One B-rep face of a CAD part: STEP entity #190.
In plain terms, the planar face has unit normal (1, 0, 0).
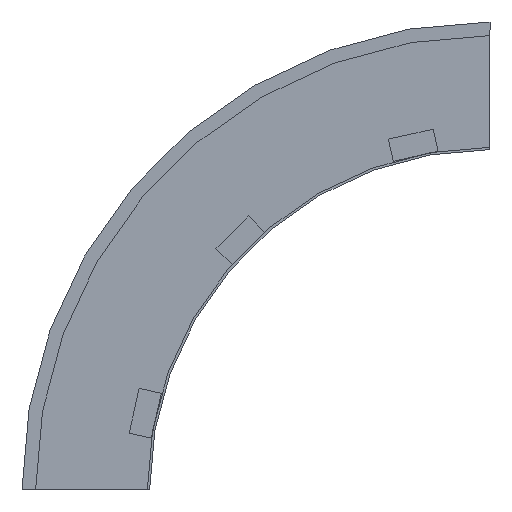
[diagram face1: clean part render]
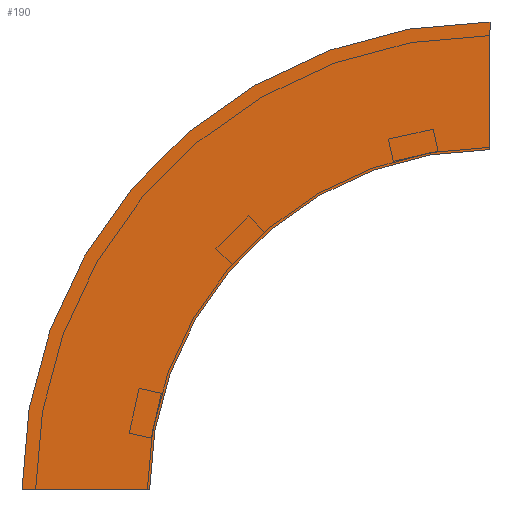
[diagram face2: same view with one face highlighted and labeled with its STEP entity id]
Its self-contained STEP definition (entity closure, numbers rounded to 3 decimals):
#4 = ORIENTED_EDGE ( 'NONE', *, *, #119, .F. ) ;
#8 = ORIENTED_EDGE ( 'NONE', *, *, #198, .T. ) ;
#22 = CARTESIAN_POINT ( 'NONE',  ( 0., 112.5, 0. ) ) ;
#48 = VERTEX_POINT ( 'NONE', #54 ) ;
#54 = CARTESIAN_POINT ( 'NONE',  ( 0., -300., 412.5 ) ) ;
#63 = DIRECTION ( 'NONE',  ( 0., 0., 1. ) ) ;
#70 = CIRCLE ( 'NONE', #253, 412.5 ) ;
#89 = AXIS2_PLACEMENT_3D ( 'NONE', #239, #536, #232 ) ;
#93 = CARTESIAN_POINT ( 'NONE',  ( 0., 0., 0. ) ) ;
#114 = VECTOR ( 'NONE', #139, 1000. ) ;
#118 = EDGE_LOOP ( 'NONE', ( #8, #143, #4, #365 ) ) ;
#119 = EDGE_CURVE ( 'NONE', #565, #291, #509, .T. ) ;
#132 = CARTESIAN_POINT ( 'NONE',  ( 0., 0., 0. ) ) ;
#136 = EDGE_CURVE ( 'NONE', #291, #48, #478, .T. ) ;
#139 = DIRECTION ( 'NONE',  ( 0., 1., 0. ) ) ;
#143 = ORIENTED_EDGE ( 'NONE', *, *, #136, .F. ) ;
#157 = PLANE ( 'NONE',  #281 ) ;
#182 = FACE_OUTER_BOUND ( 'NONE', #118, .T. ) ;
#190 = ADVANCED_FACE ( 'NONE', ( #182 ), #157, .T. ) ;
#198 = EDGE_CURVE ( 'NONE', #486, #48, #70, .T. ) ;
#232 = DIRECTION ( 'NONE',  ( 0., 1., 0. ) ) ;
#239 = CARTESIAN_POINT ( 'NONE',  ( 0., -300., 0. ) ) ;
#253 = AXIS2_PLACEMENT_3D ( 'NONE', #306, #482, #572 ) ;
#281 = AXIS2_PLACEMENT_3D ( 'NONE', #132, #311, #493 ) ;
#291 = VERTEX_POINT ( 'NONE', #520 ) ;
#306 = CARTESIAN_POINT ( 'NONE',  ( 0., -300., 0. ) ) ;
#311 = DIRECTION ( 'NONE',  ( 1., 0., 0. ) ) ;
#315 = EDGE_CURVE ( 'NONE', #565, #486, #450, .T. ) ;
#365 = ORIENTED_EDGE ( 'NONE', *, *, #315, .T. ) ;
#425 = CARTESIAN_POINT ( 'NONE',  ( 0., 0., 0. ) ) ;
#450 = LINE ( 'NONE', #93, #114 ) ;
#459 = VECTOR ( 'NONE', #63, 1000. ) ;
#466 = CARTESIAN_POINT ( 'NONE',  ( 0., -300., 300. ) ) ;
#478 = LINE ( 'NONE', #466, #459 ) ;
#482 = DIRECTION ( 'NONE',  ( 1., 0., 0. ) ) ;
#486 = VERTEX_POINT ( 'NONE', #22 ) ;
#493 = DIRECTION ( 'NONE',  ( 0., 0., -1. ) ) ;
#509 = CIRCLE ( 'NONE', #89, 300. ) ;
#520 = CARTESIAN_POINT ( 'NONE',  ( 0., -300., 300. ) ) ;
#536 = DIRECTION ( 'NONE',  ( 1., 0., 0. ) ) ;
#565 = VERTEX_POINT ( 'NONE', #425 ) ;
#572 = DIRECTION ( 'NONE',  ( 0., 1., 0. ) ) ;
